VERSION 5.7 ;
BUSBITCHARS "[]" ;
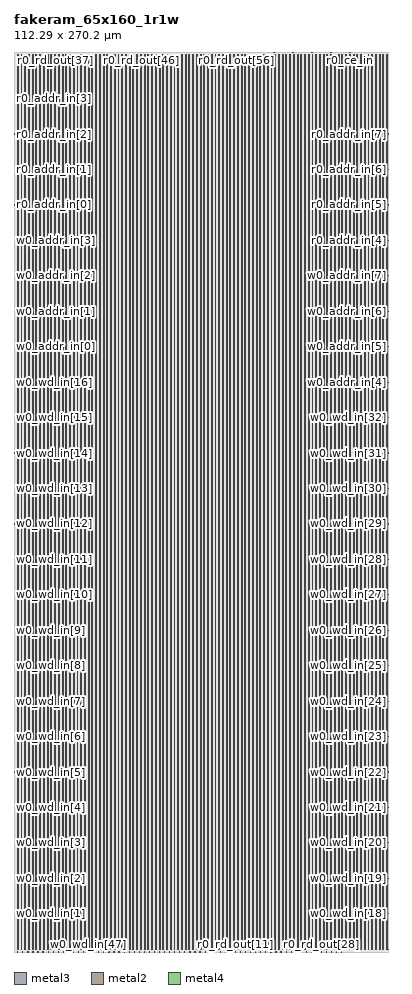
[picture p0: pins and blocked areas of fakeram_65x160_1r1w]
MACRO fakeram_65x160_1r1w
  FOREIGN fakeram_65x160_1r1w 0 0 ;
  SYMMETRY X Y R90 ;
  SIZE 112.290 BY 270.200 ;
  CLASS BLOCK ;
  PIN w0_wd_in[0]
    DIRECTION INPUT ;
    USE SIGNAL ;
    SHAPE ABUTMENT ;
    PORT
      LAYER metal3 ;
      RECT 0.000 0.805 0.210 0.875 ;
    END
  END w0_wd_in[0]
  PIN w0_wd_in[1]
    DIRECTION INPUT ;
    USE SIGNAL ;
    SHAPE ABUTMENT ;
    PORT
      LAYER metal3 ;
      RECT 0.000 11.445 0.210 11.515 ;
    END
  END w0_wd_in[1]
  PIN w0_wd_in[2]
    DIRECTION INPUT ;
    USE SIGNAL ;
    SHAPE ABUTMENT ;
    PORT
      LAYER metal3 ;
      RECT 0.000 22.085 0.210 22.155 ;
    END
  END w0_wd_in[2]
  PIN w0_wd_in[3]
    DIRECTION INPUT ;
    USE SIGNAL ;
    SHAPE ABUTMENT ;
    PORT
      LAYER metal3 ;
      RECT 0.000 32.725 0.210 32.795 ;
    END
  END w0_wd_in[3]
  PIN w0_wd_in[4]
    DIRECTION INPUT ;
    USE SIGNAL ;
    SHAPE ABUTMENT ;
    PORT
      LAYER metal3 ;
      RECT 0.000 43.365 0.210 43.435 ;
    END
  END w0_wd_in[4]
  PIN w0_wd_in[5]
    DIRECTION INPUT ;
    USE SIGNAL ;
    SHAPE ABUTMENT ;
    PORT
      LAYER metal3 ;
      RECT 0.000 54.005 0.210 54.075 ;
    END
  END w0_wd_in[5]
  PIN w0_wd_in[6]
    DIRECTION INPUT ;
    USE SIGNAL ;
    SHAPE ABUTMENT ;
    PORT
      LAYER metal3 ;
      RECT 0.000 64.645 0.210 64.715 ;
    END
  END w0_wd_in[6]
  PIN w0_wd_in[7]
    DIRECTION INPUT ;
    USE SIGNAL ;
    SHAPE ABUTMENT ;
    PORT
      LAYER metal3 ;
      RECT 0.000 75.285 0.210 75.355 ;
    END
  END w0_wd_in[7]
  PIN w0_wd_in[8]
    DIRECTION INPUT ;
    USE SIGNAL ;
    SHAPE ABUTMENT ;
    PORT
      LAYER metal3 ;
      RECT 0.000 85.925 0.210 85.995 ;
    END
  END w0_wd_in[8]
  PIN w0_wd_in[9]
    DIRECTION INPUT ;
    USE SIGNAL ;
    SHAPE ABUTMENT ;
    PORT
      LAYER metal3 ;
      RECT 0.000 96.565 0.210 96.635 ;
    END
  END w0_wd_in[9]
  PIN w0_wd_in[10]
    DIRECTION INPUT ;
    USE SIGNAL ;
    SHAPE ABUTMENT ;
    PORT
      LAYER metal3 ;
      RECT 0.000 107.205 0.210 107.275 ;
    END
  END w0_wd_in[10]
  PIN w0_wd_in[11]
    DIRECTION INPUT ;
    USE SIGNAL ;
    SHAPE ABUTMENT ;
    PORT
      LAYER metal3 ;
      RECT 0.000 117.845 0.210 117.915 ;
    END
  END w0_wd_in[11]
  PIN w0_wd_in[12]
    DIRECTION INPUT ;
    USE SIGNAL ;
    SHAPE ABUTMENT ;
    PORT
      LAYER metal3 ;
      RECT 0.000 128.485 0.210 128.555 ;
    END
  END w0_wd_in[12]
  PIN w0_wd_in[13]
    DIRECTION INPUT ;
    USE SIGNAL ;
    SHAPE ABUTMENT ;
    PORT
      LAYER metal3 ;
      RECT 0.000 139.125 0.210 139.195 ;
    END
  END w0_wd_in[13]
  PIN w0_wd_in[14]
    DIRECTION INPUT ;
    USE SIGNAL ;
    SHAPE ABUTMENT ;
    PORT
      LAYER metal3 ;
      RECT 0.000 149.765 0.210 149.835 ;
    END
  END w0_wd_in[14]
  PIN w0_wd_in[15]
    DIRECTION INPUT ;
    USE SIGNAL ;
    SHAPE ABUTMENT ;
    PORT
      LAYER metal3 ;
      RECT 0.000 160.405 0.210 160.475 ;
    END
  END w0_wd_in[15]
  PIN w0_wd_in[16]
    DIRECTION INPUT ;
    USE SIGNAL ;
    SHAPE ABUTMENT ;
    PORT
      LAYER metal3 ;
      RECT 0.000 171.045 0.210 171.115 ;
    END
  END w0_wd_in[16]
  PIN w0_wd_in[17]
    DIRECTION INPUT ;
    USE SIGNAL ;
    SHAPE ABUTMENT ;
    PORT
      LAYER metal3 ;
      RECT 112.080 0.805 112.290 0.875 ;
    END
  END w0_wd_in[17]
  PIN w0_wd_in[18]
    DIRECTION INPUT ;
    USE SIGNAL ;
    SHAPE ABUTMENT ;
    PORT
      LAYER metal3 ;
      RECT 112.080 11.445 112.290 11.515 ;
    END
  END w0_wd_in[18]
  PIN w0_wd_in[19]
    DIRECTION INPUT ;
    USE SIGNAL ;
    SHAPE ABUTMENT ;
    PORT
      LAYER metal3 ;
      RECT 112.080 22.085 112.290 22.155 ;
    END
  END w0_wd_in[19]
  PIN w0_wd_in[20]
    DIRECTION INPUT ;
    USE SIGNAL ;
    SHAPE ABUTMENT ;
    PORT
      LAYER metal3 ;
      RECT 112.080 32.725 112.290 32.795 ;
    END
  END w0_wd_in[20]
  PIN w0_wd_in[21]
    DIRECTION INPUT ;
    USE SIGNAL ;
    SHAPE ABUTMENT ;
    PORT
      LAYER metal3 ;
      RECT 112.080 43.365 112.290 43.435 ;
    END
  END w0_wd_in[21]
  PIN w0_wd_in[22]
    DIRECTION INPUT ;
    USE SIGNAL ;
    SHAPE ABUTMENT ;
    PORT
      LAYER metal3 ;
      RECT 112.080 54.005 112.290 54.075 ;
    END
  END w0_wd_in[22]
  PIN w0_wd_in[23]
    DIRECTION INPUT ;
    USE SIGNAL ;
    SHAPE ABUTMENT ;
    PORT
      LAYER metal3 ;
      RECT 112.080 64.645 112.290 64.715 ;
    END
  END w0_wd_in[23]
  PIN w0_wd_in[24]
    DIRECTION INPUT ;
    USE SIGNAL ;
    SHAPE ABUTMENT ;
    PORT
      LAYER metal3 ;
      RECT 112.080 75.285 112.290 75.355 ;
    END
  END w0_wd_in[24]
  PIN w0_wd_in[25]
    DIRECTION INPUT ;
    USE SIGNAL ;
    SHAPE ABUTMENT ;
    PORT
      LAYER metal3 ;
      RECT 112.080 85.925 112.290 85.995 ;
    END
  END w0_wd_in[25]
  PIN w0_wd_in[26]
    DIRECTION INPUT ;
    USE SIGNAL ;
    SHAPE ABUTMENT ;
    PORT
      LAYER metal3 ;
      RECT 112.080 96.565 112.290 96.635 ;
    END
  END w0_wd_in[26]
  PIN w0_wd_in[27]
    DIRECTION INPUT ;
    USE SIGNAL ;
    SHAPE ABUTMENT ;
    PORT
      LAYER metal3 ;
      RECT 112.080 107.205 112.290 107.275 ;
    END
  END w0_wd_in[27]
  PIN w0_wd_in[28]
    DIRECTION INPUT ;
    USE SIGNAL ;
    SHAPE ABUTMENT ;
    PORT
      LAYER metal3 ;
      RECT 112.080 117.845 112.290 117.915 ;
    END
  END w0_wd_in[28]
  PIN w0_wd_in[29]
    DIRECTION INPUT ;
    USE SIGNAL ;
    SHAPE ABUTMENT ;
    PORT
      LAYER metal3 ;
      RECT 112.080 128.485 112.290 128.555 ;
    END
  END w0_wd_in[29]
  PIN w0_wd_in[30]
    DIRECTION INPUT ;
    USE SIGNAL ;
    SHAPE ABUTMENT ;
    PORT
      LAYER metal3 ;
      RECT 112.080 139.125 112.290 139.195 ;
    END
  END w0_wd_in[30]
  PIN w0_wd_in[31]
    DIRECTION INPUT ;
    USE SIGNAL ;
    SHAPE ABUTMENT ;
    PORT
      LAYER metal3 ;
      RECT 112.080 149.765 112.290 149.835 ;
    END
  END w0_wd_in[31]
  PIN w0_wd_in[32]
    DIRECTION INPUT ;
    USE SIGNAL ;
    SHAPE ABUTMENT ;
    PORT
      LAYER metal3 ;
      RECT 112.080 160.405 112.290 160.475 ;
    END
  END w0_wd_in[32]
  PIN w0_wd_in[33]
    DIRECTION INPUT ;
    USE SIGNAL ;
    SHAPE ABUTMENT ;
    PORT
      LAYER metal2 ;
      RECT 1.105 0.000 1.175 0.210 ;
    END
  END w0_wd_in[33]
  PIN w0_wd_in[34]
    DIRECTION INPUT ;
    USE SIGNAL ;
    SHAPE ABUTMENT ;
    PORT
      LAYER metal2 ;
      RECT 2.625 0.000 2.695 0.210 ;
    END
  END w0_wd_in[34]
  PIN w0_wd_in[35]
    DIRECTION INPUT ;
    USE SIGNAL ;
    SHAPE ABUTMENT ;
    PORT
      LAYER metal2 ;
      RECT 4.145 0.000 4.215 0.210 ;
    END
  END w0_wd_in[35]
  PIN w0_wd_in[36]
    DIRECTION INPUT ;
    USE SIGNAL ;
    SHAPE ABUTMENT ;
    PORT
      LAYER metal2 ;
      RECT 5.665 0.000 5.735 0.210 ;
    END
  END w0_wd_in[36]
  PIN w0_wd_in[37]
    DIRECTION INPUT ;
    USE SIGNAL ;
    SHAPE ABUTMENT ;
    PORT
      LAYER metal2 ;
      RECT 7.185 0.000 7.255 0.210 ;
    END
  END w0_wd_in[37]
  PIN w0_wd_in[38]
    DIRECTION INPUT ;
    USE SIGNAL ;
    SHAPE ABUTMENT ;
    PORT
      LAYER metal2 ;
      RECT 8.705 0.000 8.775 0.210 ;
    END
  END w0_wd_in[38]
  PIN w0_wd_in[39]
    DIRECTION INPUT ;
    USE SIGNAL ;
    SHAPE ABUTMENT ;
    PORT
      LAYER metal2 ;
      RECT 10.225 0.000 10.295 0.210 ;
    END
  END w0_wd_in[39]
  PIN w0_wd_in[40]
    DIRECTION INPUT ;
    USE SIGNAL ;
    SHAPE ABUTMENT ;
    PORT
      LAYER metal2 ;
      RECT 11.745 0.000 11.815 0.210 ;
    END
  END w0_wd_in[40]
  PIN w0_wd_in[41]
    DIRECTION INPUT ;
    USE SIGNAL ;
    SHAPE ABUTMENT ;
    PORT
      LAYER metal2 ;
      RECT 13.265 0.000 13.335 0.210 ;
    END
  END w0_wd_in[41]
  PIN w0_wd_in[42]
    DIRECTION INPUT ;
    USE SIGNAL ;
    SHAPE ABUTMENT ;
    PORT
      LAYER metal2 ;
      RECT 14.785 0.000 14.855 0.210 ;
    END
  END w0_wd_in[42]
  PIN w0_wd_in[43]
    DIRECTION INPUT ;
    USE SIGNAL ;
    SHAPE ABUTMENT ;
    PORT
      LAYER metal2 ;
      RECT 16.305 0.000 16.375 0.210 ;
    END
  END w0_wd_in[43]
  PIN w0_wd_in[44]
    DIRECTION INPUT ;
    USE SIGNAL ;
    SHAPE ABUTMENT ;
    PORT
      LAYER metal2 ;
      RECT 17.825 0.000 17.895 0.210 ;
    END
  END w0_wd_in[44]
  PIN w0_wd_in[45]
    DIRECTION INPUT ;
    USE SIGNAL ;
    SHAPE ABUTMENT ;
    PORT
      LAYER metal2 ;
      RECT 19.345 0.000 19.415 0.210 ;
    END
  END w0_wd_in[45]
  PIN w0_wd_in[46]
    DIRECTION INPUT ;
    USE SIGNAL ;
    SHAPE ABUTMENT ;
    PORT
      LAYER metal2 ;
      RECT 20.865 0.000 20.935 0.210 ;
    END
  END w0_wd_in[46]
  PIN w0_wd_in[47]
    DIRECTION INPUT ;
    USE SIGNAL ;
    SHAPE ABUTMENT ;
    PORT
      LAYER metal2 ;
      RECT 22.385 0.000 22.455 0.210 ;
    END
  END w0_wd_in[47]
  PIN w0_wd_in[48]
    DIRECTION INPUT ;
    USE SIGNAL ;
    SHAPE ABUTMENT ;
    PORT
      LAYER metal2 ;
      RECT 23.905 0.000 23.975 0.210 ;
    END
  END w0_wd_in[48]
  PIN w0_wd_in[49]
    DIRECTION INPUT ;
    USE SIGNAL ;
    SHAPE ABUTMENT ;
    PORT
      LAYER metal2 ;
      RECT 25.425 0.000 25.495 0.210 ;
    END
  END w0_wd_in[49]
  PIN w0_wd_in[50]
    DIRECTION INPUT ;
    USE SIGNAL ;
    SHAPE ABUTMENT ;
    PORT
      LAYER metal2 ;
      RECT 26.945 0.000 27.015 0.210 ;
    END
  END w0_wd_in[50]
  PIN w0_wd_in[51]
    DIRECTION INPUT ;
    USE SIGNAL ;
    SHAPE ABUTMENT ;
    PORT
      LAYER metal2 ;
      RECT 28.465 0.000 28.535 0.210 ;
    END
  END w0_wd_in[51]
  PIN w0_wd_in[52]
    DIRECTION INPUT ;
    USE SIGNAL ;
    SHAPE ABUTMENT ;
    PORT
      LAYER metal2 ;
      RECT 29.985 0.000 30.055 0.210 ;
    END
  END w0_wd_in[52]
  PIN w0_wd_in[53]
    DIRECTION INPUT ;
    USE SIGNAL ;
    SHAPE ABUTMENT ;
    PORT
      LAYER metal2 ;
      RECT 31.505 0.000 31.575 0.210 ;
    END
  END w0_wd_in[53]
  PIN w0_wd_in[54]
    DIRECTION INPUT ;
    USE SIGNAL ;
    SHAPE ABUTMENT ;
    PORT
      LAYER metal2 ;
      RECT 33.025 0.000 33.095 0.210 ;
    END
  END w0_wd_in[54]
  PIN w0_wd_in[55]
    DIRECTION INPUT ;
    USE SIGNAL ;
    SHAPE ABUTMENT ;
    PORT
      LAYER metal2 ;
      RECT 34.545 0.000 34.615 0.210 ;
    END
  END w0_wd_in[55]
  PIN w0_wd_in[56]
    DIRECTION INPUT ;
    USE SIGNAL ;
    SHAPE ABUTMENT ;
    PORT
      LAYER metal2 ;
      RECT 36.065 0.000 36.135 0.210 ;
    END
  END w0_wd_in[56]
  PIN w0_wd_in[57]
    DIRECTION INPUT ;
    USE SIGNAL ;
    SHAPE ABUTMENT ;
    PORT
      LAYER metal2 ;
      RECT 37.585 0.000 37.655 0.210 ;
    END
  END w0_wd_in[57]
  PIN w0_wd_in[58]
    DIRECTION INPUT ;
    USE SIGNAL ;
    SHAPE ABUTMENT ;
    PORT
      LAYER metal2 ;
      RECT 39.105 0.000 39.175 0.210 ;
    END
  END w0_wd_in[58]
  PIN w0_wd_in[59]
    DIRECTION INPUT ;
    USE SIGNAL ;
    SHAPE ABUTMENT ;
    PORT
      LAYER metal2 ;
      RECT 40.625 0.000 40.695 0.210 ;
    END
  END w0_wd_in[59]
  PIN w0_wd_in[60]
    DIRECTION INPUT ;
    USE SIGNAL ;
    SHAPE ABUTMENT ;
    PORT
      LAYER metal2 ;
      RECT 42.145 0.000 42.215 0.210 ;
    END
  END w0_wd_in[60]
  PIN w0_wd_in[61]
    DIRECTION INPUT ;
    USE SIGNAL ;
    SHAPE ABUTMENT ;
    PORT
      LAYER metal2 ;
      RECT 43.665 0.000 43.735 0.210 ;
    END
  END w0_wd_in[61]
  PIN w0_wd_in[62]
    DIRECTION INPUT ;
    USE SIGNAL ;
    SHAPE ABUTMENT ;
    PORT
      LAYER metal2 ;
      RECT 45.185 0.000 45.255 0.210 ;
    END
  END w0_wd_in[62]
  PIN w0_wd_in[63]
    DIRECTION INPUT ;
    USE SIGNAL ;
    SHAPE ABUTMENT ;
    PORT
      LAYER metal2 ;
      RECT 46.705 0.000 46.775 0.210 ;
    END
  END w0_wd_in[63]
  PIN w0_wd_in[64]
    DIRECTION INPUT ;
    USE SIGNAL ;
    SHAPE ABUTMENT ;
    PORT
      LAYER metal2 ;
      RECT 48.225 0.000 48.295 0.210 ;
    END
  END w0_wd_in[64]
  PIN r0_rd_out[0]
    DIRECTION OUTPUT ;
    USE SIGNAL ;
    SHAPE ABUTMENT ;
    PORT
      LAYER metal2 ;
      RECT 49.745 0.000 49.815 0.210 ;
    END
  END r0_rd_out[0]
  PIN r0_rd_out[1]
    DIRECTION OUTPUT ;
    USE SIGNAL ;
    SHAPE ABUTMENT ;
    PORT
      LAYER metal2 ;
      RECT 51.265 0.000 51.335 0.210 ;
    END
  END r0_rd_out[1]
  PIN r0_rd_out[2]
    DIRECTION OUTPUT ;
    USE SIGNAL ;
    SHAPE ABUTMENT ;
    PORT
      LAYER metal2 ;
      RECT 52.785 0.000 52.855 0.210 ;
    END
  END r0_rd_out[2]
  PIN r0_rd_out[3]
    DIRECTION OUTPUT ;
    USE SIGNAL ;
    SHAPE ABUTMENT ;
    PORT
      LAYER metal2 ;
      RECT 54.305 0.000 54.375 0.210 ;
    END
  END r0_rd_out[3]
  PIN r0_rd_out[4]
    DIRECTION OUTPUT ;
    USE SIGNAL ;
    SHAPE ABUTMENT ;
    PORT
      LAYER metal2 ;
      RECT 55.825 0.000 55.895 0.210 ;
    END
  END r0_rd_out[4]
  PIN r0_rd_out[5]
    DIRECTION OUTPUT ;
    USE SIGNAL ;
    SHAPE ABUTMENT ;
    PORT
      LAYER metal2 ;
      RECT 57.345 0.000 57.415 0.210 ;
    END
  END r0_rd_out[5]
  PIN r0_rd_out[6]
    DIRECTION OUTPUT ;
    USE SIGNAL ;
    SHAPE ABUTMENT ;
    PORT
      LAYER metal2 ;
      RECT 58.865 0.000 58.935 0.210 ;
    END
  END r0_rd_out[6]
  PIN r0_rd_out[7]
    DIRECTION OUTPUT ;
    USE SIGNAL ;
    SHAPE ABUTMENT ;
    PORT
      LAYER metal2 ;
      RECT 60.385 0.000 60.455 0.210 ;
    END
  END r0_rd_out[7]
  PIN r0_rd_out[8]
    DIRECTION OUTPUT ;
    USE SIGNAL ;
    SHAPE ABUTMENT ;
    PORT
      LAYER metal2 ;
      RECT 61.905 0.000 61.975 0.210 ;
    END
  END r0_rd_out[8]
  PIN r0_rd_out[9]
    DIRECTION OUTPUT ;
    USE SIGNAL ;
    SHAPE ABUTMENT ;
    PORT
      LAYER metal2 ;
      RECT 63.425 0.000 63.495 0.210 ;
    END
  END r0_rd_out[9]
  PIN r0_rd_out[10]
    DIRECTION OUTPUT ;
    USE SIGNAL ;
    SHAPE ABUTMENT ;
    PORT
      LAYER metal2 ;
      RECT 64.945 0.000 65.015 0.210 ;
    END
  END r0_rd_out[10]
  PIN r0_rd_out[11]
    DIRECTION OUTPUT ;
    USE SIGNAL ;
    SHAPE ABUTMENT ;
    PORT
      LAYER metal2 ;
      RECT 66.465 0.000 66.535 0.210 ;
    END
  END r0_rd_out[11]
  PIN r0_rd_out[12]
    DIRECTION OUTPUT ;
    USE SIGNAL ;
    SHAPE ABUTMENT ;
    PORT
      LAYER metal2 ;
      RECT 67.985 0.000 68.055 0.210 ;
    END
  END r0_rd_out[12]
  PIN r0_rd_out[13]
    DIRECTION OUTPUT ;
    USE SIGNAL ;
    SHAPE ABUTMENT ;
    PORT
      LAYER metal2 ;
      RECT 69.505 0.000 69.575 0.210 ;
    END
  END r0_rd_out[13]
  PIN r0_rd_out[14]
    DIRECTION OUTPUT ;
    USE SIGNAL ;
    SHAPE ABUTMENT ;
    PORT
      LAYER metal2 ;
      RECT 71.025 0.000 71.095 0.210 ;
    END
  END r0_rd_out[14]
  PIN r0_rd_out[15]
    DIRECTION OUTPUT ;
    USE SIGNAL ;
    SHAPE ABUTMENT ;
    PORT
      LAYER metal2 ;
      RECT 72.545 0.000 72.615 0.210 ;
    END
  END r0_rd_out[15]
  PIN r0_rd_out[16]
    DIRECTION OUTPUT ;
    USE SIGNAL ;
    SHAPE ABUTMENT ;
    PORT
      LAYER metal2 ;
      RECT 74.065 0.000 74.135 0.210 ;
    END
  END r0_rd_out[16]
  PIN r0_rd_out[17]
    DIRECTION OUTPUT ;
    USE SIGNAL ;
    SHAPE ABUTMENT ;
    PORT
      LAYER metal2 ;
      RECT 75.585 0.000 75.655 0.210 ;
    END
  END r0_rd_out[17]
  PIN r0_rd_out[18]
    DIRECTION OUTPUT ;
    USE SIGNAL ;
    SHAPE ABUTMENT ;
    PORT
      LAYER metal2 ;
      RECT 77.105 0.000 77.175 0.210 ;
    END
  END r0_rd_out[18]
  PIN r0_rd_out[19]
    DIRECTION OUTPUT ;
    USE SIGNAL ;
    SHAPE ABUTMENT ;
    PORT
      LAYER metal2 ;
      RECT 78.625 0.000 78.695 0.210 ;
    END
  END r0_rd_out[19]
  PIN r0_rd_out[20]
    DIRECTION OUTPUT ;
    USE SIGNAL ;
    SHAPE ABUTMENT ;
    PORT
      LAYER metal2 ;
      RECT 80.145 0.000 80.215 0.210 ;
    END
  END r0_rd_out[20]
  PIN r0_rd_out[21]
    DIRECTION OUTPUT ;
    USE SIGNAL ;
    SHAPE ABUTMENT ;
    PORT
      LAYER metal2 ;
      RECT 81.665 0.000 81.735 0.210 ;
    END
  END r0_rd_out[21]
  PIN r0_rd_out[22]
    DIRECTION OUTPUT ;
    USE SIGNAL ;
    SHAPE ABUTMENT ;
    PORT
      LAYER metal2 ;
      RECT 83.185 0.000 83.255 0.210 ;
    END
  END r0_rd_out[22]
  PIN r0_rd_out[23]
    DIRECTION OUTPUT ;
    USE SIGNAL ;
    SHAPE ABUTMENT ;
    PORT
      LAYER metal2 ;
      RECT 84.705 0.000 84.775 0.210 ;
    END
  END r0_rd_out[23]
  PIN r0_rd_out[24]
    DIRECTION OUTPUT ;
    USE SIGNAL ;
    SHAPE ABUTMENT ;
    PORT
      LAYER metal2 ;
      RECT 86.225 0.000 86.295 0.210 ;
    END
  END r0_rd_out[24]
  PIN r0_rd_out[25]
    DIRECTION OUTPUT ;
    USE SIGNAL ;
    SHAPE ABUTMENT ;
    PORT
      LAYER metal2 ;
      RECT 87.745 0.000 87.815 0.210 ;
    END
  END r0_rd_out[25]
  PIN r0_rd_out[26]
    DIRECTION OUTPUT ;
    USE SIGNAL ;
    SHAPE ABUTMENT ;
    PORT
      LAYER metal2 ;
      RECT 89.265 0.000 89.335 0.210 ;
    END
  END r0_rd_out[26]
  PIN r0_rd_out[27]
    DIRECTION OUTPUT ;
    USE SIGNAL ;
    SHAPE ABUTMENT ;
    PORT
      LAYER metal2 ;
      RECT 90.785 0.000 90.855 0.210 ;
    END
  END r0_rd_out[27]
  PIN r0_rd_out[28]
    DIRECTION OUTPUT ;
    USE SIGNAL ;
    SHAPE ABUTMENT ;
    PORT
      LAYER metal2 ;
      RECT 92.305 0.000 92.375 0.210 ;
    END
  END r0_rd_out[28]
  PIN r0_rd_out[29]
    DIRECTION OUTPUT ;
    USE SIGNAL ;
    SHAPE ABUTMENT ;
    PORT
      LAYER metal2 ;
      RECT 93.825 0.000 93.895 0.210 ;
    END
  END r0_rd_out[29]
  PIN r0_rd_out[30]
    DIRECTION OUTPUT ;
    USE SIGNAL ;
    SHAPE ABUTMENT ;
    PORT
      LAYER metal2 ;
      RECT 95.345 0.000 95.415 0.210 ;
    END
  END r0_rd_out[30]
  PIN r0_rd_out[31]
    DIRECTION OUTPUT ;
    USE SIGNAL ;
    SHAPE ABUTMENT ;
    PORT
      LAYER metal2 ;
      RECT 96.865 0.000 96.935 0.210 ;
    END
  END r0_rd_out[31]
  PIN r0_rd_out[32]
    DIRECTION OUTPUT ;
    USE SIGNAL ;
    SHAPE ABUTMENT ;
    PORT
      LAYER metal2 ;
      RECT 98.385 0.000 98.455 0.210 ;
    END
  END r0_rd_out[32]
  PIN r0_rd_out[33]
    DIRECTION OUTPUT ;
    USE SIGNAL ;
    SHAPE ABUTMENT ;
    PORT
      LAYER metal2 ;
      RECT 1.105 269.990 1.175 270.200 ;
    END
  END r0_rd_out[33]
  PIN r0_rd_out[34]
    DIRECTION OUTPUT ;
    USE SIGNAL ;
    SHAPE ABUTMENT ;
    PORT
      LAYER metal2 ;
      RECT 3.955 269.990 4.025 270.200 ;
    END
  END r0_rd_out[34]
  PIN r0_rd_out[35]
    DIRECTION OUTPUT ;
    USE SIGNAL ;
    SHAPE ABUTMENT ;
    PORT
      LAYER metal2 ;
      RECT 6.805 269.990 6.875 270.200 ;
    END
  END r0_rd_out[35]
  PIN r0_rd_out[36]
    DIRECTION OUTPUT ;
    USE SIGNAL ;
    SHAPE ABUTMENT ;
    PORT
      LAYER metal2 ;
      RECT 9.655 269.990 9.725 270.200 ;
    END
  END r0_rd_out[36]
  PIN r0_rd_out[37]
    DIRECTION OUTPUT ;
    USE SIGNAL ;
    SHAPE ABUTMENT ;
    PORT
      LAYER metal2 ;
      RECT 12.505 269.990 12.575 270.200 ;
    END
  END r0_rd_out[37]
  PIN r0_rd_out[38]
    DIRECTION OUTPUT ;
    USE SIGNAL ;
    SHAPE ABUTMENT ;
    PORT
      LAYER metal2 ;
      RECT 15.355 269.990 15.425 270.200 ;
    END
  END r0_rd_out[38]
  PIN r0_rd_out[39]
    DIRECTION OUTPUT ;
    USE SIGNAL ;
    SHAPE ABUTMENT ;
    PORT
      LAYER metal2 ;
      RECT 18.205 269.990 18.275 270.200 ;
    END
  END r0_rd_out[39]
  PIN r0_rd_out[40]
    DIRECTION OUTPUT ;
    USE SIGNAL ;
    SHAPE ABUTMENT ;
    PORT
      LAYER metal2 ;
      RECT 21.055 269.990 21.125 270.200 ;
    END
  END r0_rd_out[40]
  PIN r0_rd_out[41]
    DIRECTION OUTPUT ;
    USE SIGNAL ;
    SHAPE ABUTMENT ;
    PORT
      LAYER metal2 ;
      RECT 23.905 269.990 23.975 270.200 ;
    END
  END r0_rd_out[41]
  PIN r0_rd_out[42]
    DIRECTION OUTPUT ;
    USE SIGNAL ;
    SHAPE ABUTMENT ;
    PORT
      LAYER metal2 ;
      RECT 26.755 269.990 26.825 270.200 ;
    END
  END r0_rd_out[42]
  PIN r0_rd_out[43]
    DIRECTION OUTPUT ;
    USE SIGNAL ;
    SHAPE ABUTMENT ;
    PORT
      LAYER metal2 ;
      RECT 29.605 269.990 29.675 270.200 ;
    END
  END r0_rd_out[43]
  PIN r0_rd_out[44]
    DIRECTION OUTPUT ;
    USE SIGNAL ;
    SHAPE ABUTMENT ;
    PORT
      LAYER metal2 ;
      RECT 32.455 269.990 32.525 270.200 ;
    END
  END r0_rd_out[44]
  PIN r0_rd_out[45]
    DIRECTION OUTPUT ;
    USE SIGNAL ;
    SHAPE ABUTMENT ;
    PORT
      LAYER metal2 ;
      RECT 35.305 269.990 35.375 270.200 ;
    END
  END r0_rd_out[45]
  PIN r0_rd_out[46]
    DIRECTION OUTPUT ;
    USE SIGNAL ;
    SHAPE ABUTMENT ;
    PORT
      LAYER metal2 ;
      RECT 38.155 269.990 38.225 270.200 ;
    END
  END r0_rd_out[46]
  PIN r0_rd_out[47]
    DIRECTION OUTPUT ;
    USE SIGNAL ;
    SHAPE ABUTMENT ;
    PORT
      LAYER metal2 ;
      RECT 41.005 269.990 41.075 270.200 ;
    END
  END r0_rd_out[47]
  PIN r0_rd_out[48]
    DIRECTION OUTPUT ;
    USE SIGNAL ;
    SHAPE ABUTMENT ;
    PORT
      LAYER metal2 ;
      RECT 43.855 269.990 43.925 270.200 ;
    END
  END r0_rd_out[48]
  PIN r0_rd_out[49]
    DIRECTION OUTPUT ;
    USE SIGNAL ;
    SHAPE ABUTMENT ;
    PORT
      LAYER metal2 ;
      RECT 46.705 269.990 46.775 270.200 ;
    END
  END r0_rd_out[49]
  PIN r0_rd_out[50]
    DIRECTION OUTPUT ;
    USE SIGNAL ;
    SHAPE ABUTMENT ;
    PORT
      LAYER metal2 ;
      RECT 49.555 269.990 49.625 270.200 ;
    END
  END r0_rd_out[50]
  PIN r0_rd_out[51]
    DIRECTION OUTPUT ;
    USE SIGNAL ;
    SHAPE ABUTMENT ;
    PORT
      LAYER metal2 ;
      RECT 52.405 269.990 52.475 270.200 ;
    END
  END r0_rd_out[51]
  PIN r0_rd_out[52]
    DIRECTION OUTPUT ;
    USE SIGNAL ;
    SHAPE ABUTMENT ;
    PORT
      LAYER metal2 ;
      RECT 55.255 269.990 55.325 270.200 ;
    END
  END r0_rd_out[52]
  PIN r0_rd_out[53]
    DIRECTION OUTPUT ;
    USE SIGNAL ;
    SHAPE ABUTMENT ;
    PORT
      LAYER metal2 ;
      RECT 58.105 269.990 58.175 270.200 ;
    END
  END r0_rd_out[53]
  PIN r0_rd_out[54]
    DIRECTION OUTPUT ;
    USE SIGNAL ;
    SHAPE ABUTMENT ;
    PORT
      LAYER metal2 ;
      RECT 60.955 269.990 61.025 270.200 ;
    END
  END r0_rd_out[54]
  PIN r0_rd_out[55]
    DIRECTION OUTPUT ;
    USE SIGNAL ;
    SHAPE ABUTMENT ;
    PORT
      LAYER metal2 ;
      RECT 63.805 269.990 63.875 270.200 ;
    END
  END r0_rd_out[55]
  PIN r0_rd_out[56]
    DIRECTION OUTPUT ;
    USE SIGNAL ;
    SHAPE ABUTMENT ;
    PORT
      LAYER metal2 ;
      RECT 66.655 269.990 66.725 270.200 ;
    END
  END r0_rd_out[56]
  PIN r0_rd_out[57]
    DIRECTION OUTPUT ;
    USE SIGNAL ;
    SHAPE ABUTMENT ;
    PORT
      LAYER metal2 ;
      RECT 69.505 269.990 69.575 270.200 ;
    END
  END r0_rd_out[57]
  PIN r0_rd_out[58]
    DIRECTION OUTPUT ;
    USE SIGNAL ;
    SHAPE ABUTMENT ;
    PORT
      LAYER metal2 ;
      RECT 72.355 269.990 72.425 270.200 ;
    END
  END r0_rd_out[58]
  PIN r0_rd_out[59]
    DIRECTION OUTPUT ;
    USE SIGNAL ;
    SHAPE ABUTMENT ;
    PORT
      LAYER metal2 ;
      RECT 75.205 269.990 75.275 270.200 ;
    END
  END r0_rd_out[59]
  PIN r0_rd_out[60]
    DIRECTION OUTPUT ;
    USE SIGNAL ;
    SHAPE ABUTMENT ;
    PORT
      LAYER metal2 ;
      RECT 78.055 269.990 78.125 270.200 ;
    END
  END r0_rd_out[60]
  PIN r0_rd_out[61]
    DIRECTION OUTPUT ;
    USE SIGNAL ;
    SHAPE ABUTMENT ;
    PORT
      LAYER metal2 ;
      RECT 80.905 269.990 80.975 270.200 ;
    END
  END r0_rd_out[61]
  PIN r0_rd_out[62]
    DIRECTION OUTPUT ;
    USE SIGNAL ;
    SHAPE ABUTMENT ;
    PORT
      LAYER metal2 ;
      RECT 83.755 269.990 83.825 270.200 ;
    END
  END r0_rd_out[62]
  PIN r0_rd_out[63]
    DIRECTION OUTPUT ;
    USE SIGNAL ;
    SHAPE ABUTMENT ;
    PORT
      LAYER metal2 ;
      RECT 86.605 269.990 86.675 270.200 ;
    END
  END r0_rd_out[63]
  PIN r0_rd_out[64]
    DIRECTION OUTPUT ;
    USE SIGNAL ;
    SHAPE ABUTMENT ;
    PORT
      LAYER metal2 ;
      RECT 89.455 269.990 89.525 270.200 ;
    END
  END r0_rd_out[64]
  PIN w0_addr_in[0]
    DIRECTION INPUT ;
    USE SIGNAL ;
    SHAPE ABUTMENT ;
    PORT
      LAYER metal3 ;
      RECT 0.000 181.685 0.210 181.755 ;
    END
  END w0_addr_in[0]
  PIN w0_addr_in[1]
    DIRECTION INPUT ;
    USE SIGNAL ;
    SHAPE ABUTMENT ;
    PORT
      LAYER metal3 ;
      RECT 0.000 192.325 0.210 192.395 ;
    END
  END w0_addr_in[1]
  PIN w0_addr_in[2]
    DIRECTION INPUT ;
    USE SIGNAL ;
    SHAPE ABUTMENT ;
    PORT
      LAYER metal3 ;
      RECT 0.000 202.965 0.210 203.035 ;
    END
  END w0_addr_in[2]
  PIN w0_addr_in[3]
    DIRECTION INPUT ;
    USE SIGNAL ;
    SHAPE ABUTMENT ;
    PORT
      LAYER metal3 ;
      RECT 0.000 213.605 0.210 213.675 ;
    END
  END w0_addr_in[3]
  PIN w0_addr_in[4]
    DIRECTION INPUT ;
    USE SIGNAL ;
    SHAPE ABUTMENT ;
    PORT
      LAYER metal3 ;
      RECT 112.080 171.045 112.290 171.115 ;
    END
  END w0_addr_in[4]
  PIN w0_addr_in[5]
    DIRECTION INPUT ;
    USE SIGNAL ;
    SHAPE ABUTMENT ;
    PORT
      LAYER metal3 ;
      RECT 112.080 181.685 112.290 181.755 ;
    END
  END w0_addr_in[5]
  PIN w0_addr_in[6]
    DIRECTION INPUT ;
    USE SIGNAL ;
    SHAPE ABUTMENT ;
    PORT
      LAYER metal3 ;
      RECT 112.080 192.325 112.290 192.395 ;
    END
  END w0_addr_in[6]
  PIN w0_addr_in[7]
    DIRECTION INPUT ;
    USE SIGNAL ;
    SHAPE ABUTMENT ;
    PORT
      LAYER metal3 ;
      RECT 112.080 202.965 112.290 203.035 ;
    END
  END w0_addr_in[7]
  PIN r0_addr_in[0]
    DIRECTION INPUT ;
    USE SIGNAL ;
    SHAPE ABUTMENT ;
    PORT
      LAYER metal3 ;
      RECT 0.000 224.245 0.210 224.315 ;
    END
  END r0_addr_in[0]
  PIN r0_addr_in[1]
    DIRECTION INPUT ;
    USE SIGNAL ;
    SHAPE ABUTMENT ;
    PORT
      LAYER metal3 ;
      RECT 0.000 234.885 0.210 234.955 ;
    END
  END r0_addr_in[1]
  PIN r0_addr_in[2]
    DIRECTION INPUT ;
    USE SIGNAL ;
    SHAPE ABUTMENT ;
    PORT
      LAYER metal3 ;
      RECT 0.000 245.525 0.210 245.595 ;
    END
  END r0_addr_in[2]
  PIN r0_addr_in[3]
    DIRECTION INPUT ;
    USE SIGNAL ;
    SHAPE ABUTMENT ;
    PORT
      LAYER metal3 ;
      RECT 0.000 256.165 0.210 256.235 ;
    END
  END r0_addr_in[3]
  PIN r0_addr_in[4]
    DIRECTION INPUT ;
    USE SIGNAL ;
    SHAPE ABUTMENT ;
    PORT
      LAYER metal3 ;
      RECT 112.080 213.605 112.290 213.675 ;
    END
  END r0_addr_in[4]
  PIN r0_addr_in[5]
    DIRECTION INPUT ;
    USE SIGNAL ;
    SHAPE ABUTMENT ;
    PORT
      LAYER metal3 ;
      RECT 112.080 224.245 112.290 224.315 ;
    END
  END r0_addr_in[5]
  PIN r0_addr_in[6]
    DIRECTION INPUT ;
    USE SIGNAL ;
    SHAPE ABUTMENT ;
    PORT
      LAYER metal3 ;
      RECT 112.080 234.885 112.290 234.955 ;
    END
  END r0_addr_in[6]
  PIN r0_addr_in[7]
    DIRECTION INPUT ;
    USE SIGNAL ;
    SHAPE ABUTMENT ;
    PORT
      LAYER metal3 ;
      RECT 112.080 245.525 112.290 245.595 ;
    END
  END r0_addr_in[7]
  PIN w0_we_in
    DIRECTION INPUT ;
    USE SIGNAL ;
    SHAPE ABUTMENT ;
    PORT
      LAYER metal2 ;
      RECT 92.305 269.990 92.375 270.200 ;
    END
  END w0_we_in
  PIN w0_ce_in
    DIRECTION INPUT ;
    USE SIGNAL ;
    SHAPE ABUTMENT ;
    PORT
      LAYER metal2 ;
      RECT 95.155 269.990 95.225 270.200 ;
    END
  END w0_ce_in
  PIN w0_clk
    DIRECTION INPUT ;
    USE SIGNAL ;
    SHAPE ABUTMENT ;
    PORT
      LAYER metal2 ;
      RECT 98.005 269.990 98.075 270.200 ;
    END
  END w0_clk
  PIN r0_ce_in
    DIRECTION INPUT ;
    USE SIGNAL ;
    SHAPE ABUTMENT ;
    PORT
      LAYER metal2 ;
      RECT 100.855 269.990 100.925 270.200 ;
    END
  END r0_ce_in
  PIN r0_clk
    DIRECTION INPUT ;
    USE SIGNAL ;
    SHAPE ABUTMENT ;
    PORT
      LAYER metal2 ;
      RECT 103.705 269.990 103.775 270.200 ;
    END
  END r0_clk
  PIN VSS
    DIRECTION INOUT ;
    USE GROUND ;
    PORT
      LAYER metal4 ;
      RECT 1.000 0.840 1.280 269.360 ;
      RECT 3.240 0.840 3.520 269.360 ;
      RECT 5.480 0.840 5.760 269.360 ;
      RECT 7.720 0.840 8.000 269.360 ;
      RECT 9.960 0.840 10.240 269.360 ;
      RECT 12.200 0.840 12.480 269.360 ;
      RECT 14.440 0.840 14.720 269.360 ;
      RECT 16.680 0.840 16.960 269.360 ;
      RECT 18.920 0.840 19.200 269.360 ;
      RECT 21.160 0.840 21.440 269.360 ;
      RECT 23.400 0.840 23.680 269.360 ;
      RECT 25.640 0.840 25.920 269.360 ;
      RECT 27.880 0.840 28.160 269.360 ;
      RECT 30.120 0.840 30.400 269.360 ;
      RECT 32.360 0.840 32.640 269.360 ;
      RECT 34.600 0.840 34.880 269.360 ;
      RECT 36.840 0.840 37.120 269.360 ;
      RECT 39.080 0.840 39.360 269.360 ;
      RECT 41.320 0.840 41.600 269.360 ;
      RECT 43.560 0.840 43.840 269.360 ;
      RECT 45.800 0.840 46.080 269.360 ;
      RECT 48.040 0.840 48.320 269.360 ;
      RECT 50.280 0.840 50.560 269.360 ;
      RECT 52.520 0.840 52.800 269.360 ;
      RECT 54.760 0.840 55.040 269.360 ;
      RECT 57.000 0.840 57.280 269.360 ;
      RECT 59.240 0.840 59.520 269.360 ;
      RECT 61.480 0.840 61.760 269.360 ;
      RECT 63.720 0.840 64.000 269.360 ;
      RECT 65.960 0.840 66.240 269.360 ;
      RECT 68.200 0.840 68.480 269.360 ;
      RECT 70.440 0.840 70.720 269.360 ;
      RECT 72.680 0.840 72.960 269.360 ;
      RECT 74.920 0.840 75.200 269.360 ;
      RECT 77.160 0.840 77.440 269.360 ;
      RECT 79.400 0.840 79.680 269.360 ;
      RECT 81.640 0.840 81.920 269.360 ;
      RECT 83.880 0.840 84.160 269.360 ;
      RECT 86.120 0.840 86.400 269.360 ;
      RECT 88.360 0.840 88.640 269.360 ;
      RECT 90.600 0.840 90.880 269.360 ;
      RECT 92.840 0.840 93.120 269.360 ;
      RECT 95.080 0.840 95.360 269.360 ;
      RECT 97.320 0.840 97.600 269.360 ;
      RECT 99.560 0.840 99.840 269.360 ;
      RECT 101.800 0.840 102.080 269.360 ;
      RECT 104.040 0.840 104.320 269.360 ;
      RECT 106.280 0.840 106.560 269.360 ;
      RECT 108.520 0.840 108.800 269.360 ;
      RECT 110.760 0.840 111.040 269.360 ;
    END
  END VSS
  PIN VDD
    DIRECTION INOUT ;
    USE POWER ;
    PORT
      LAYER metal4 ;
      RECT 2.120 0.840 2.400 269.360 ;
      RECT 4.360 0.840 4.640 269.360 ;
      RECT 6.600 0.840 6.880 269.360 ;
      RECT 8.840 0.840 9.120 269.360 ;
      RECT 11.080 0.840 11.360 269.360 ;
      RECT 13.320 0.840 13.600 269.360 ;
      RECT 15.560 0.840 15.840 269.360 ;
      RECT 17.800 0.840 18.080 269.360 ;
      RECT 20.040 0.840 20.320 269.360 ;
      RECT 22.280 0.840 22.560 269.360 ;
      RECT 24.520 0.840 24.800 269.360 ;
      RECT 26.760 0.840 27.040 269.360 ;
      RECT 29.000 0.840 29.280 269.360 ;
      RECT 31.240 0.840 31.520 269.360 ;
      RECT 33.480 0.840 33.760 269.360 ;
      RECT 35.720 0.840 36.000 269.360 ;
      RECT 37.960 0.840 38.240 269.360 ;
      RECT 40.200 0.840 40.480 269.360 ;
      RECT 42.440 0.840 42.720 269.360 ;
      RECT 44.680 0.840 44.960 269.360 ;
      RECT 46.920 0.840 47.200 269.360 ;
      RECT 49.160 0.840 49.440 269.360 ;
      RECT 51.400 0.840 51.680 269.360 ;
      RECT 53.640 0.840 53.920 269.360 ;
      RECT 55.880 0.840 56.160 269.360 ;
      RECT 58.120 0.840 58.400 269.360 ;
      RECT 60.360 0.840 60.640 269.360 ;
      RECT 62.600 0.840 62.880 269.360 ;
      RECT 64.840 0.840 65.120 269.360 ;
      RECT 67.080 0.840 67.360 269.360 ;
      RECT 69.320 0.840 69.600 269.360 ;
      RECT 71.560 0.840 71.840 269.360 ;
      RECT 73.800 0.840 74.080 269.360 ;
      RECT 76.040 0.840 76.320 269.360 ;
      RECT 78.280 0.840 78.560 269.360 ;
      RECT 80.520 0.840 80.800 269.360 ;
      RECT 82.760 0.840 83.040 269.360 ;
      RECT 85.000 0.840 85.280 269.360 ;
      RECT 87.240 0.840 87.520 269.360 ;
      RECT 89.480 0.840 89.760 269.360 ;
      RECT 91.720 0.840 92.000 269.360 ;
      RECT 93.960 0.840 94.240 269.360 ;
      RECT 96.200 0.840 96.480 269.360 ;
      RECT 98.440 0.840 98.720 269.360 ;
      RECT 100.680 0.840 100.960 269.360 ;
      RECT 102.920 0.840 103.200 269.360 ;
      RECT 105.160 0.840 105.440 269.360 ;
      RECT 107.400 0.840 107.680 269.360 ;
      RECT 109.640 0.840 109.920 269.360 ;
      RECT 111.880 0.840 112.160 269.360 ;
    END
  END VDD
  OBS
    LAYER metal1 ;
    RECT 0 0 112.290 270.200 ;
    LAYER metal2 ;
    RECT 0 0 112.290 270.200 ;
    LAYER metal3 ;
    RECT 0 0 112.290 270.200 ;
    LAYER metal4 ;
    RECT 0 0 112.290 270.200 ;
    LAYER OVERLAP ;
    RECT 0 0 112.290 270.200 ;
  END
END fakeram_65x160_1r1w

END LIBRARY
